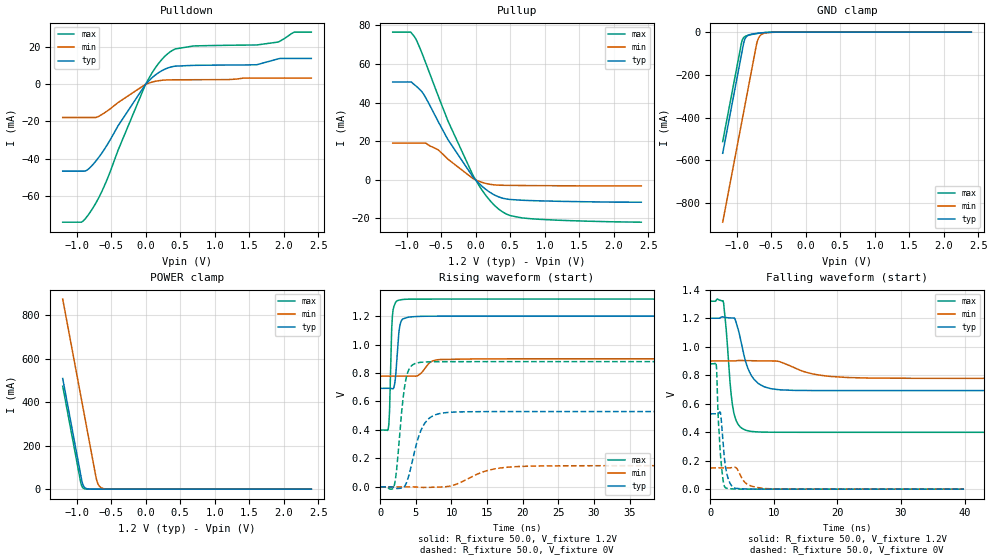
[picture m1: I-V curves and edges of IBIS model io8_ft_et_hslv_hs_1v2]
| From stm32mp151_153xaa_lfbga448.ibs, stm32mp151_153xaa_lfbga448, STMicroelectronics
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[Model]   io8_ft_et_hslv_hs_1v2
Model_type I/O
Polarity   Non-Inverting
Enable   Active-Low
| CAP_THRESHOLD on pad IOFT is "UDTCAPC" :
| Rising=20.00f vddiom   Falling=80.00f vddiom
| C_comp min and max val. don't necessarily correlate with the min and max pvt
| but are the smallest and greatest pad capacitance found.
| var   typ   min   max
C_comp   3.10945pF  3.08840pF  3.12935pF
|C_comp_pullup   1.82175pF  1.58940pF  1.75355pF
|C_comp_pulldown   1.28770pF  1.49900pF  1.37580pF
Vinl = 360.0mV
Vinh = 792.0mV
Vmeas = 600.0mV   | Reference voltage for timing measurements
Cref  = 50.0pF   | Timing specification test load capacitance value
Rref  = 100.0MOhm   | Timing specification test load resistance value
Vref  = 0V   | Timing specification test load voltage
[Model Spec]
| TIME_THRESHOLD on pin ZIV11 is "CMOS" :
| Rising=40.00f vdd   Falling=60.00f vdd
Vinl 463.60000mV 362.60000mV 506.60000mV
Vinh 741.40000mV 545.40000mV 817.40000mV
| variable   typ   min   max
[Temperature Range] 25.0 140.0 -40.0
| variable   typ   min   max
[Voltage Range] 1.2V 900.0mV 1.32V
| variable   typ   min   max
[POWER Clamp Reference] 1.2V 900.0mV 1.32V
| variable   typ   min   max
[GND Clamp Reference] 0V 0V 0V
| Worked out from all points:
|   slope of the pulldown table from 0 to 0.18 V, typ, clamps not added: 30 ohm
|   slope of the pullup table from 0 to 0.18 V, typ, clamps not added: 31.1 ohm
|   GND clamp passes 1 mA (typ) near -0.52 V on its own axis
|   POWER clamp passes 1 mA (typ) near -0.83 V on its own axis
|   rising waveform, R_fixture 50.0, V_fixture 1.2V: 20-80 % time 469ps typ, 1.22ns min, 303ps max; typ from 0.692 V to 1.2 V
|   falling waveform, R_fixture 50.0, V_fixture 1.2V: 20-80 % time 1.99ns typ, 4.89ns min, 1.04ns max; typ from 1.2 V to 0.692 V
|   rising waveform, R_fixture 50.0, V_fixture 0V: 20-80 % time 1.81ns typ, 4.17ns min, 1.01ns max; typ from 0 V to 0.529 V
|   falling waveform, R_fixture 50.0, V_fixture 0V: 20-80 % time 776ps typ, 1.52ns min, 630ps max; typ from 0.529 V to 0 V
[POWER Clamp]
-1.2V     508.8mA    874.1mA    473.5mA
-940mV    66.83mA    432.1mA    31.5mA
-930mV    49.83mA    415.1mA    19.15mA
-910mV    22.88mA    381.1mA    7.077mA
-880mV    7.117mA    330.1mA    1.59mA
-830mV    1.017mA    245.1mA    132uA
-720mV    14.05uA    58.12mA    554nA
-690mV    4.373uA    25.03mA    124.8nA
-650mV    922.5nA    8.136mA    17.23nA
-600mV    132.6nA    1.998mA    1.565nA
-490mV    2.857nA    90.92uA    111.8pA
2.4V      0A         0A         0A
[GND Clamp]
-1.2V     -567.2mA   -889.7mA   -512.2mA
-930mV    -108.2mA   -430.7mA   -53.23mA
-920mV    -91.21mA   -413.7mA   -40.49mA
-890mV    -43.51mA   -362.7mA   -23.59mA
-860mV    -22.57mA   -311.7mA   -17.89mA
-810mV    -12.11mA   -226.7mA   -13.23mA
-710mV    -6.053mA   -57.05mA   -7.064mA
-680mV    -4.908mA   -27.37mA   -5.632mA
-640mV    -3.605mA   -11.51mA   -3.985mA
-560mV    -1.665mA   -3.218mA   -1.61mA
-360mV    -34.72uA   -209.4uA   -9.248uA
2.4V      3.415nA    1.206uA    162.7pA
| variable   typ   min   max
[Pullup Reference] 1.2V 900.0mV 1.32V
| variable   typ   min   max
[Pulldown Reference] 0V 0V 0V
[Pullup]
-1.2V     50.71mA    18.99mA    76.55mA
-940mV    50.71mA    18.99mA    76.55mA
-870mV    48.83mA    18.99mA    73.29mA
-760mV    44.8mA     18.99mA    64.11mA
-550mV    30.82mA    15.7mA     44.31mA
-400mV    20.81mA    10.68mA    30.51mA
-40mV     1.605mA    702.6uA    2.512mA
160mV     -5.268mA   -1.975mA   -8.606mA
350mV     -9.04mA    -2.783mA   -15.59mA
510mV     -10.21mA   -2.889mA   -18.61mA
750mV     -10.7mA    -2.975mA   -20.01mA
2.4V      -11.6mA    -3.141mA   -21.96mA
[Pulldown]
-1.2V     -46.7mA    -17.86mA   -74.13mA
-930mV    -46.7mA    -17.86mA   -74.13mA
-770mV    -43.45mA   -17.86mA   -66.94mA
-580mV    -33.98mA   -14.99mA   -53.18mA
0V        0A         -6pA       0A
170mV     5.742mA    1.792mA    10.3mA
340mV     8.972mA    2.348mA    16.97mA
690mV     10.15mA    2.431mA    20.56mA
1.61V     10.49mA    3.333mA    21.11mA
1.92V     13.63mA    3.333mA    22.69mA
2.15V     13.87mA    3.333mA    27.93mA
2.4V      13.87mA    3.333mA    28.03mA
[Ramp]
dV/dt_r 317.41819mV/1.81281ns 89.26304mV/4.16545ns 528.12961mV/1.00938ns
dV/dt_f 304.66736mV/1.99296ns 73.18611mV/4.89232ns 552.41142mV/1.03926ns
R_load = 50.0
| Removed startup time: 0s 0s 0s  .
| Removed end time: 39.9ns.
[Rising Waveform]
R_fixture   = 50.0
V_fixture   = 1.2V
V_fixture_min = 900.0mV
V_fixture_max = 1.32V
0s        692.2mV    778mV      399.3mV
1.2ns     692.5mV    778.1mV    437.4mV
1.6ns     690.8mV    778.1mV    1.109V
1.7ns     689mV      778.1mV    1.198V
2.1ns     752.6mV    778.1mV    1.292V
2.4ns     954.5mV    778.1mV    1.309V
2.9ns     1.16V      778.1mV    1.315V
4ns       1.193V     778.2mV    1.319V
8.3ns     1.2V       894.6mV    1.32V
39.9ns    1.2V       900mV      1.32V
| Removed startup time: 0s 0s 0s  .
| Removed end time: 199.9ns.
[Falling Waveform]
R_fixture   = 50.0
V_fixture   = 1.2V
V_fixture_min = 900.0mV
V_fixture_max = 1.32V
0s        1.2V       900mV      1.32V
2.1ns     1.208V     900mV      1.305V
3.2ns     1.202V     899.8mV    702.1mV
3.9ns     1.193V     900.6mV    502.9mV
5.6ns     889.8mV    902.1mV    413.8mV
6.7ns     782mV      901.2mV    404.4mV
10.8ns    698.1mV    896.7mV    399.5mV
16.1ns    692.5mV    809.2mV    399.3mV
24.9ns    692.2mV    780.2mV    399.3mV
199.9ns   692.2mV    778mV      399.3mV
| Removed startup time: 0s 0s 0s  .
| Removed end time: 199.9ns.
[Rising Waveform]
R_fixture   = 50.0
V_fixture   = 0V
V_fixture_min = 0V
V_fixture_max = 0V
0s        -204.6nV   193.4nV    -4.045uV
1.9ns     -5.602mV   -484.1nV   -2.479mV
2.3ns     -11.76mV   -2.2uV     123.3mV
3.2ns     -6.005mV   -45.89uV   622.1mV
3.7ns     30.96mV    1.074uV    778.9mV
5.9ns     417mV      -4.443mV   876.4mV
8.8ns     519.1mV    -1.016mV   879.7mV
15.7ns    528.7mV    122.4mV    880.1mV
22.2ns    528.9mV    146.3mV    880.2mV
199.9ns   529mV      148.8mV    880.2mV
| Removed startup time: 0s 0s 0s  .
| Removed end time: 39.9ns.
[Falling Waveform]
R_fixture   = 50.0
V_fixture   = 0V
V_fixture_min = 0V
V_fixture_max = 0V
0s        529mV      148.8mV    880.2mV
900ps     529.2mV    148.8mV    891.4mV
1ns       529mV      148.8mV    843.5mV
1.3ns     531.9mV    148.8mV    455.6mV
1.6ns     537.4mV    148.8mV    242.7mV
2.4ns     155.1mV    148.8mV    9.407mV
4.1ns     5.555mV    149.4mV    870.3uV
5.6ns     1.589mV    41.23mV    223.6uV
8.5ns     236.4uV    5.158mV    32.75uV
39.9ns    57.39nV    1.38uV     34.8nV
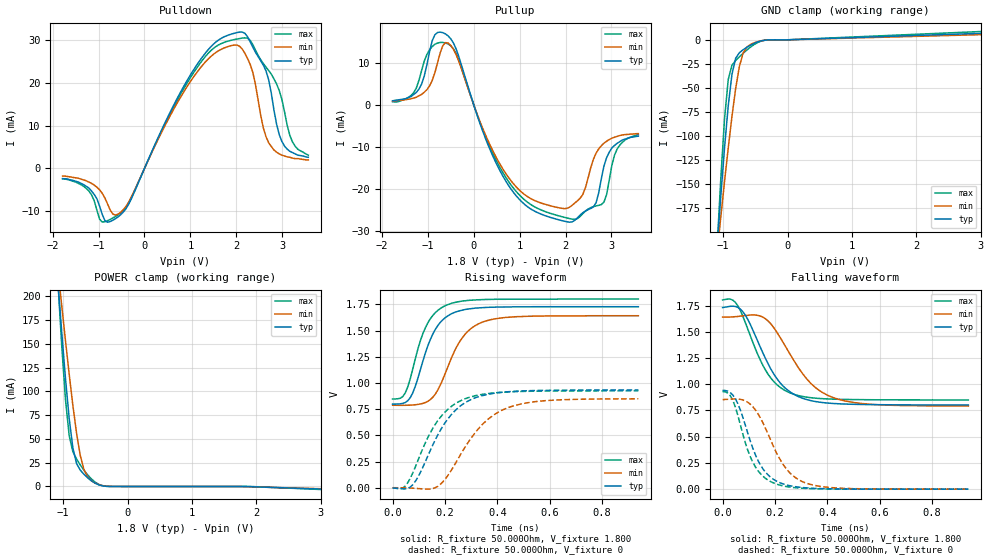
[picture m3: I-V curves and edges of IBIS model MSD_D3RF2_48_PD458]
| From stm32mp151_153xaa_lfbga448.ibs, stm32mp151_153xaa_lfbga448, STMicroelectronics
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[Model] MSD_D3RF2_48_PD458
Model_type   I/O
C_comp 2.372pF   2.291pF   2.493pF
Vinh = 1.150V
Vinl = 650.000mV
Vmeas = 900.000mV
Vref = 900.000mV
[Model Spec]
Vinh   1.150V   1.100V   1.200V
Vinl   650.000mV   600.000mV   700.000mV
Vmeas   900.000mV   850.000mV   950.000mV
Vref   900.000mV   850.000mV   950.000mV
[Temperature Range]   25.000   125.000   -40.000
[Voltage Range]   1.800V   1.700V   1.900V
[GND Clamp Reference]   0.00V   0.00V   0.00V
[Pulldown Reference]   0.00V   0.00V   0.00V
[POWER Clamp Reference]   1.800V   1.700V   1.900V
[Pullup Reference]   1.800V   1.700V   1.900V
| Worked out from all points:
|   slope of the pulldown table from 0 to 0.27 V, typ, clamps not added: 41 ohm
|   slope of the pullup table from 0 to 0.27 V, typ, clamps not added: 32.3 ohm
|   GND clamp passes 1 mA (typ) near -0.40 V on its own axis
|   POWER clamp passes 1 mA (typ) near -0.41 V on its own axis
|   rising waveform, R_fixture 50.000Ohm, V_fixture 1.800: 20-80 % time 82.4ps typ, 101ps min, 76.2ps max; typ from 0.798 V to 1.73 V
|   rising waveform, R_fixture 50.000Ohm, V_fixture 0: 20-80 % time 130ps typ, 153ps min, 123ps max; typ from -0.002 V to 0.934 V
|   falling waveform, R_fixture 50.000Ohm, V_fixture 1.800: 20-80 % time 119ps typ, 144ps min, 107ps max; typ from 1.73 V to 0.802 V
|   falling waveform, R_fixture 50.000Ohm, V_fixture 0: 20-80 % time 87.5ps typ, 108ps min, 79.1ps max; typ from 0.942 V to 0 V
[GND Clamp]
-1.785V   -902mA     -689.4mA   -1.211A
-1.094V   -215mA     -221.2mA   -215.8mA
-1.036V   -162.1mA   -183.9mA   -143.8mA
-978.8mV  -112.5mA   -147.5mA   -82.44mA
-921.2mV  -68.78mA   -112.6mA   -41.33mA
-863.6mV  -35.99mA   -79.83mA   -26.49mA
-806.1mV  -19.21mA   -50.81mA   -21.54mA
-748.5mV  -13.41mA   -27.96mA   -17.69mA
-690.9mV  -10.37mA   -13.94mA   -14.08mA
-575.8mV  -5.623mA   -4.825mA   -7.6mA
-287.9mV  -74.28uA   -124.4uA   -59.6uA
3.57V     8.01mA     6.376mA    10.24mA
[Power Clamp]
-1.77V    883.4mA    690.5mA    1.16A
-1.079V   212.7mA    226.7mA    212.7mA
-1.021V   161.3mA    189.6mA    147.2mA
-963.6mV  113.3mA    153.2mA    91.32mA
-906.1mV  71.44mA    118mA      53.27mA
-848.5mV  40.26mA    84.97mA    36.49mA
-790.9mV  24mA       55.59mA    28.76mA
-733.3mV  17.15mA    32.36mA    22.54mA
-618.2mV  9.062mA    9.82mA     12.07mA
-503mV    3.471mA    3.563mA    4.523mA
-272.7mV  29uA       101.1uA    30.42uA
3.585V    -4.055mA   -3.446mA   -4.875mA
[Pulldown]
-1.785V   -2.4mA     -1.8mA     -2.4mA
-1.209V   -4.6mA     -3.2mA     -5.3mA
-921.2mV  -10.72mA   -5.8mA     -12.52mA
-690.9mV  -12.11mA   -10.65mA   -11.59mA
-518.2mV  -10.82mA   -10.23mA   -10.35mA
1.094V    23.43mA    21.75mA    22.75mA
2.073V    31.84mA    28.54mA    30.34mA
2.361V    28.32mA    22.42mA    28.91mA
2.706V    20.69mA    6mA        22.85mA
2.994V    6.3mA      3.1mA      16.1mA
3.224V    3.7mA      2.4mA      6.2mA
3.57V     2.6mA      2mA        3.1mA
[Pullup]
-1.77V    1mA        900uA      773.7uA
-1.309V   2.5mA      1.647mA    2.937mA
-1.021V   9.6mA      3.642mA    12.02mA
-848.5mV  16.66mA    7.674mA    14.42mA
-618.2mV  16.89mA    14.82mA    14.75mA
763.6mV   -19.22mA   -17.31mA   -18.28mA
2.03V     -27.75mA   -24.55mA   -26.84mA
2.376V    -25.59mA   -21.22mA   -25.8mA
2.606V    -24.21mA   -12.89mA   -24.15mA
2.836V    -14.5mA    -9.058mA   -23.07mA
3.124V    -9.1mA     -7.453mA   -10.44mA
3.585V    -7.4mA     -6.8mA     -7.074mA
[Ramp]
R_load=50.000Ohm
dV/dt_r   557.580mV/107.000ps  509.759mV/128.500ps  562.260mV/100.500ps
dV/dt_f   557.580mV/104.000ps  509.759mV/126.500ps  562.260mV/93.500ps
[Rising waveform]
R_fixture=50.000Ohm
V_fixture=1.800
V_fixture_min=1.700
V_fixture_max=1.900
0s        798.2mV    787.5mV    847.4mV
39ps      804.9mV    786.6mV    870.3mV
68ps      861.5mV    788.2mV    1.045V
96ps      1.039V     794.9mV    1.318V
125ps     1.284V     813mV      1.525V
163ps     1.51V      892.8mV    1.67V
202ps     1.624V     1.097V     1.738V
269ps     1.696V     1.44V      1.782V
355ps     1.72V      1.59V      1.796V
938ps     1.727V     1.641V     1.8V
[Rising waveform]
R_fixture=50.000Ohm
V_fixture=0
0s        -1.68mV    601.3uV    -1.967mV
39ps      -10.41mV   -415.5uV   -1.572mV
77ps      28.99mV    -4.057mV   140mV
135ps     305.6mV    -13.28mV   481mV
173ps     506mV      14.28mV    641.9mV
221ps     687.9mV    154.3mV    769.4mV
278ps     813.5mV    392.7mV    850.1mV
365ps     892.3mV    655.4mV    898.8mV
451ps     917.9mV    773.3mV    915.2mV
938ps     933.5mV    848.5mV    924.7mV
[Falling waveform]
R_fixture=50.000Ohm
V_fixture=1.800
V_fixture_min=1.700
V_fixture_max=1.900
0s        1.731V     1.64V      1.803V
29ps      1.743V     1.641V     1.812V
58ps      1.733V     1.646V     1.749V
96ps      1.619V     1.657V     1.528V
154ps     1.298V     1.639V     1.179V
211ps     1.041V     1.481V     988.1mV
259ps     924.8mV    1.28V      916.3mV
336ps     844.7mV    1.01V      872.1mV
441ps     814.2mV    857.4mV    856.8mV
938ps     802.3mV    792.5mV    850.5mV
[Falling waveform]
R_fixture=50.000Ohm
V_fixture=0
0s        941.6mV    853.6mV    930.2mV
20ps      934.1mV    856.8mV    916mV
39ps      897.6mV    859.4mV    847.6mV
68ps      754.3mV    856.1mV    612.3mV
106ps     457.6mV    809.4mV    307.6mV
154ps     193.7mV    632.3mV    123.7mV
202ps     81.87mV    365.7mV    51.88mV
269ps     27mV       127.4mV    16.2mV
355ps     7.249mV    34.12mV    3.841mV
938ps     21.21uV    36.29uV    0V
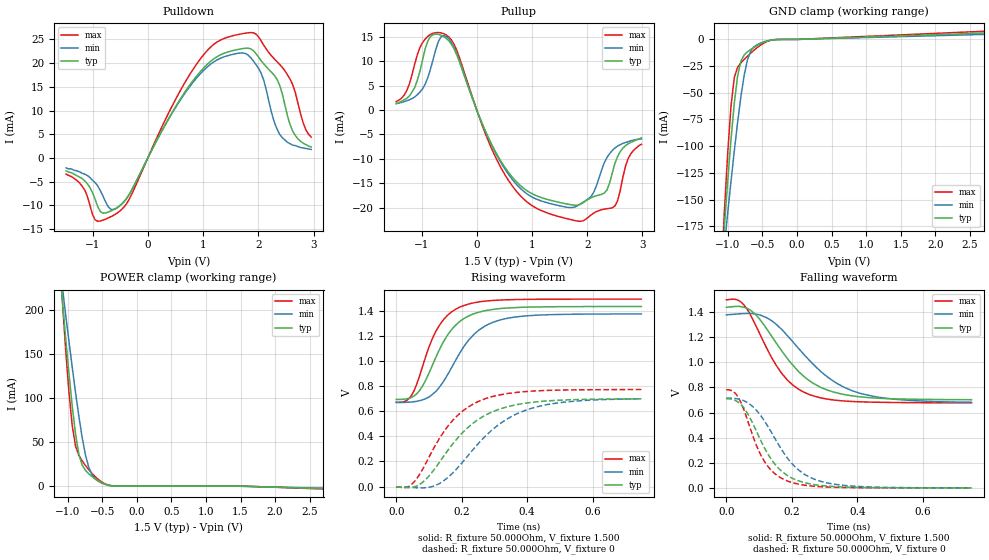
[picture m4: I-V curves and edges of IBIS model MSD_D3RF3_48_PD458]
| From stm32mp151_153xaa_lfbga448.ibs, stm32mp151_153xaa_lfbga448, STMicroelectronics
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[Model] MSD_D3RF3_48_PD458
Model_type   I/O
C_comp 2.385pF   2.303pF   2.507pF
Vinh = 925.000mV
Vinl = 575.000mV
Vmeas = 750.000mV
Vref = 750.000mV
[Model Spec]
Vinh   925.000mV   888.000mV   963.000mV
Vinl   575.000mV   538.000mV   613.000mV
Vmeas   750.000mV   713.000mV   788.000mV
Vref   750.000mV   713.000mV   788.000mV
[Temperature Range]   25.000   125.000   -40.000
[Voltage Range]   1.500V   1.425V   1.575V
[GND Clamp Reference]   0.00V   0.00V   0.00V
[Pulldown Reference]   0.00V   0.00V   0.00V
[POWER Clamp Reference]   1.500V   1.425V   1.575V
[Pullup Reference]   1.500V   1.425V   1.575V
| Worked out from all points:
|   slope of the pulldown table from 0 to 0.225 V, typ, clamps not added: 44.1 ohm
|   slope of the pullup table from 0 to 0.225 V, typ, clamps not added: 37.5 ohm
|   GND clamp passes 1 mA (typ) near -0.40 V on its own axis
|   POWER clamp passes 1 mA (typ) near -0.41 V on its own axis
|   rising waveform, R_fixture 50.000Ohm, V_fixture 1.500: 20-80 % time 93.1ps typ, 110ps min, 79ps max; typ from 0.694 V to 1.44 V
|   rising waveform, R_fixture 50.000Ohm, V_fixture 0: 20-80 % time 149ps typ, 169ps min, 128ps max; typ from -0.003 V to 0.699 V
|   falling waveform, R_fixture 50.000Ohm, V_fixture 1.500: 20-80 % time 139ps typ, 168ps min, 111ps max; typ from 1.44 V to 0.703 V
|   falling waveform, R_fixture 50.000Ohm, V_fixture 0: 20-80 % time 95.2ps typ, 114ps min, 78.5ps max; typ from 0.711 V to 0 V
[GND Clamp]
-1.48V    -594.6mA   -480.3mA   -764mA
-1.098V   -218.6mA   -223.7mA   -220.8mA
-1.05V    -174.4mA   -192.7mA   -160.1mA
-1.002V   -132.3mA   -162.2mA   -105.6mA
-954.6mV  -93.15mA   -132.6mA   -61.94mA
-906.8mV  -59.31mA   -104.2mA   -35.51mA
-859.1mV  -34.06mA   -77.39mA   -25.96mA
-811.4mV  -20.13mA   -53.27mA   -21.92mA
-715.9mV  -11.58mA   -18.88mA   -15.63mA
-572.7mV  -5.513mA   -4.72mA    -7.447mA
-334.1mV  -249.6uA   -317.8uA   -254.1uA
2.959V    6.512mA    5.126mA    8.372mA
[Power Clamp]
-1.459V   578.2mA    479.5mA    723.7mA
-1.077V   211.3mA    225.7mA    210.8mA
-1.03V    168.5mA    194.9mA    156mA
-981.8mV  127.8mA    164.6mA    107.1mA
-934.1mV  90.77mA    134.9mA    68.64mA
-886.4mV  59.26mA    106.4mA    45.51mA
-838.6mV  36.4mA     79.58mA    34.92mA
-743.2mV  18.03mA    35.67mA    23.54mA
-647.7mV  10.86mA    12.93mA    14.5mA
-552.3mV  5.551mA    5.488mA    7.32mA
-313.6mV  97.21uA    230.9uA    114.2uA
2.98V     -3.313mA   -2.778mA   -4.023mA
[Pulldown]
-1.48V    -2.7mA     -2.1mA     -3.4mA
-1.145V   -4.8mA     -3.4mA     -6.7mA
-954.6mV  -8.71mA    -5.2mA     -13.05mA
-811.4mV  -11.64mA   -8.06mA    -13.11mA
-525mV    -10.19mA   -10.28mA   -11.37mA
906.8mV   17.61mA    17.2mA     20.18mA
1.766V    23.15mA    22.05mA    26.32mA
2.052V    20.52mA    17.86mA    24.7mA
2.386V    15.37mA    5mA        19.75mA
2.625V    5.6mA      2.7mA      15.4mA
2.816V    3.1mA      2.1mA      7.3mA
2.959V    2.3mA      1.8mA      4.4mA
[Pullup]
-1.459V   1.3mA      1.357mA    1.729mA
-1.125V   4.6mA      2.671mA    9.4mA
-981.8mV  10.3mA     4.357mA    13.84mA
-838.6mV  15.06mA    8.386mA    15.51mA
-552.3mV  14.69mA    15.08mA    15.38mA
640.9mV   -13.71mA   -14.18mA   -15.51mA
1.834V    -19.47mA   -19.55mA   -22.76mA
2.12V     -17.72mA   -16.78mA   -21.08mA
2.311V    -16.98mA   -10.74mA   -20.29mA
2.502V    -10.9mA    -7.771mA   -19.63mA
2.741V    -6.9mA     -6.486mA   -9.928mA
2.98V     -5.7mA     -5.9mA     -7.014mA
[Ramp]
R_load=50.000Ohm
dV/dt_r   430.230mV/121.500ps  420.209mV/140.000ps  477.210mV/104.000ps
dV/dt_f   430.230mV/118.000ps  420.209mV/142.500ps  477.210mV/95.500ps
[Rising waveform]
R_fixture=50.000Ohm
V_fixture=1.500
V_fixture_min=1.425
V_fixture_max=1.575
0s        694.2mV    669.6mV    671.7mV
39ps      703.1mV    672.3mV    699.9mV
69ps      757.5mV    683mV      862.7mV
100ps     903.4mV    713.2mV    1.111V
123ps     1.041V     762.5mV    1.246V
154ps     1.196V     878.5mV    1.358V
192ps     1.311V     1.054V     1.428V
253ps     1.39V      1.248V     1.472V
330ps     1.421V     1.336V     1.488V
749ps     1.435V     1.376V     1.494V
[Rising waveform]
R_fixture=50.000Ohm
V_fixture=0
0s        -3.058mV   -1.782mV   -3.355mV
31ps      -8.593mV   -5.329mV   -6.138mV
54ps      -4.024mV   -8.678mV   34.03mV
85ps      43.65mV    -10.32mV   158mV
131ps     189.5mV    21.94mV    378.7mV
199ps     419.2mV    182.5mV    593.7mV
261ps     551.7mV    370.8mV    689mV
337ps     633.9mV    535.7mV    740mV
429ps     675.3mV    635.1mV    762.7mV
749ps     698.9mV    698.9mV    773.3mV
[Falling waveform]
R_fixture=50.000Ohm
V_fixture=1.500
V_fixture_min=1.425
V_fixture_max=1.575
0s        1.439V     1.379V     1.498V
46ps      1.444V     1.388V     1.478V
85ps      1.391V     1.387V     1.321V
123ps     1.268V     1.356V     1.115V
169ps     1.093V     1.263V     913.1mV
245ps     870.5mV    1.041V     753.3mV
330ps     761.6mV    845.7mV    699.6mV
414ps     724mV      749.5mV    685.3mV
513ps     709.5mV    706.3mV    680.3mV
749ps     702.6mV    681.9mV    677.5mV
[Falling waveform]
R_fixture=50.000Ohm
V_fixture=0
0s        710.9mV    714.5mV    782mV
23ps      702.1mV    713.3mV    764.8mV
39ps      677.1mV    707mV      710.1mV
85ps      490.6mV    636.7mV    385.5mV
108ps     362.2mV    565mV      248.4mV
131ps     252.4mV    472.1mV    158.1mV
184ps     103.2mV    247.1mV    57.7mV
238ps     42.31mV    109.3mV    21.92mV
322ps     11.63mV    32.46mV    5.154mV
749ps     79.97uV    222.5uV    -2.137uV
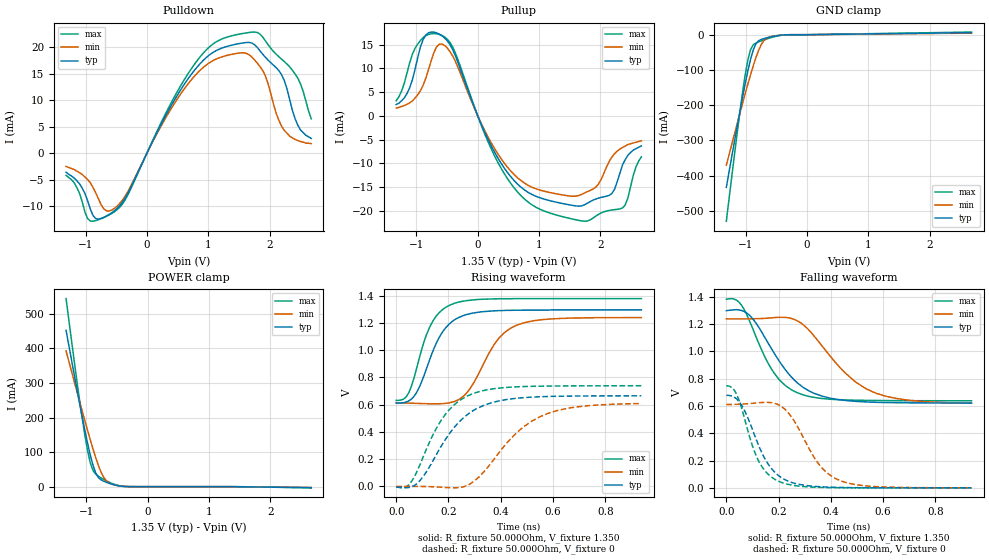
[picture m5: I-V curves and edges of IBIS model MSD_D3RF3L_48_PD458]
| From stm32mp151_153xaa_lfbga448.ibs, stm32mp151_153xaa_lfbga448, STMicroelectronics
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[Model] MSD_D3RF3L_48_PD458
Model_type   I/O
C_comp 2.393pF   2.308pF   2.516pF
Vinh = 810.000mV
Vinl = 540.000mV
Vmeas = 675.000mV
Vref = 675.000mV
[Model Spec]
Vinh   810.000mV   777.000mV   860.000mV
Vinl   540.000mV   507.000mV   590.000mV
Vmeas   675.000mV   642.000mV   725.000mV
Vref   675.000mV   642.000mV   725.000mV
[Temperature Range]   25.000   125.000   -40.000
[Voltage Range]   1.350V   1.283V   1.450V
[GND Clamp Reference]   0.00V   0.00V   0.00V
[Pulldown Reference]   0.00V   0.00V   0.00V
[POWER Clamp Reference]   1.350V   1.283V   1.450V
[Pullup Reference]   1.350V   1.283V   1.450V
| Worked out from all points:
|   slope of the pulldown table from 0 to 0.203 V, typ, clamps not added: 42.2 ohm
|   slope of the pullup table from 0 to 0.203 V, typ, clamps not added: 34.5 ohm
|   GND clamp passes 1 mA (typ) near -0.40 V on its own axis
|   POWER clamp passes 1 mA (typ) near -0.41 V on its own axis
|   rising waveform, R_fixture 50.000Ohm, V_fixture 1.350: 20-80 % time 94.1ps typ, 117ps min, 79.7ps max; typ from 0.612 V to 1.29 V
|   rising waveform, R_fixture 50.000Ohm, V_fixture 0: 20-80 % time 152ps typ, 184ps min, 130ps max; typ from -0.004 V to 0.665 V
|   falling waveform, R_fixture 50.000Ohm, V_fixture 1.350: 20-80 % time 152ps typ, 185ps min, 119ps max; typ from 1.3 V to 0.621 V
|   falling waveform, R_fixture 50.000Ohm, V_fixture 0: 20-80 % time 99.8ps typ, 118ps min, 82.4ps max; typ from 0.678 V to 0 V
[GND Clamp]
-1.318V   -433.4mA   -370.8mA   -529.5mA
-1.142V   -261.1mA   -253.1mA   -280.7mA
-1.055V   -178.6mA   -195.6mA   -165.7mA
-1.011V   -139.5mA   -167.5mA   -114.5mA
-966.7mV  -102.7mA   -140mA     -71.69mA
-922.7mV  -69.83mA   -113.5mA   -42.04mA
-878.8mV  -43.2mA    -88.17mA   -28.64mA
-834.9mV  -25.59mA   -64.74mA   -23.69mA
-790.9mV  -17.08mA   -44.07mA   -20.49mA
-703mV    -10.94mA   -16.13mA   -14.83mA
-527.3mV  -3.964mA   -3.359mA   -5.286mA
2.68V     5.803mA    4.518mA    7.521mA
[Power Clamp]
-1.33V    452.5mA    393mA      544.4mA
-1.111V   242.2mA    247.4mA    251.2mA
-1.023V   162.6mA    190.5mA    148.3mA
-978.8mV  125.4mA    162.5mA    103.8mA
-934.9mV  91.31mA    135.3mA    68.32mA
-890.9mV  61.93mA    108.9mA    46.71mA
-847mV    39.6mA     84.01mA    36.22mA
-803mV    26.26mA    61.23mA    30.15mA
-715.1mV  15.61mA    26.48mA    20.68mA
-671.2mV  12.4mA     16.4mA     16.54mA
-407.6mV  894uA      1.169mA    1.092mA
2.668V    -2.917mA   -2.431mA   -3.468mA
[Pulldown]
-1.318V   -3.6mA     -2.5mA     -4.2mA
-1.098V   -5.8mA     -3.7mA     -7.6mA
-922.7mV  -10.54mA   -5.6mA     -12.83mA
-703mV    -12.12mA   -10.54mA   -12.17mA
-483.3mV  -10.41mA   -9.976mA   -10.65mA
790.9mV   15.9mA     14.77mA    17.06mA
1.582V    20.87mA    18.98mA    22.68mA
1.889V    18.71mA    15.62mA    21.96mA
2.197V    14.84mA    5.1mA      17.77mA
2.329V    10.1mA     3.2mA      16.32mA
2.461V    5.3mA      2.4mA      14.2mA
2.68V     2.8mA      1.8mA      6.5mA
[Pullup]
-1.33V    2.4mA      1.652mA    3.207mA
-1.023V   9.8mA      3.767mA    14.27mA
-890.9mV  16.12mA    6.482mA    16.52mA
-715.1mV  17.65mA    13.35mA    17.35mA
-451.5mV  14.98mA    13.54mA    15.46mA
295.4mV   -8.125mA   -7.33mA    -8.964mA
910.6mV   -16.72mA   -15.17mA   -18.95mA
1.702V    -18.92mA   -16.49mA   -22.14mA
1.965V    -17.33mA   -14.42mA   -20.77mA
2.185V    -16.37mA   -8.694mA   -19.82mA
2.361V    -10.3mA    -6.643mA   -19.39mA
2.668V    -6.3mA     -5.248mA   -8.621mA
[Ramp]
R_load=50.000Ohm
dV/dt_r   402.030mV/123.500ps  370.259mV/152.000ps  443.850mV/105.500ps
dV/dt_f   402.030mV/125.500ps  370.319mV/153.500ps  443.850mV/100.500ps
[Rising waveform]
R_fixture=50.000Ohm
V_fixture=1.350
V_fixture_min=1.283
V_fixture_max=1.450
0s        611.7mV    614mV      631.4mV
39ps      620mV      612mV      659.5mV
77ps      685.9mV    609.6mV    858.1mV
135ps     966.3mV    606.4mV    1.195V
173ps     1.121V     607.4mV    1.29V
211ps     1.205V     617.5mV    1.335V
278ps     1.265V     705.5mV    1.365V
374ps     1.288V     1.039V     1.376V
460ps     1.293V     1.182V     1.378V
938ps     1.295V     1.239V     1.378V
[Rising waveform]
R_fixture=50.000Ohm
V_fixture=0
0s        -4.091mV   598.5uV    -4.132mV
48ps      -7.821mV   818.6uV    11.8mV
87ps      35.92mV    511.1uV    142.1mV
135ps     169.4mV    -1.636mV   357.1mV
183ps     329.4mV    -6.49mV    515.8mV
288ps     548.8mV    25.88mV    677mV
460ps     647mV      392mV      731mV
547ps     658mV      509mV      735.5mV
681ps     663.3mV    581.2mV    737.9mV
938ps     665.1mV    608.3mV    739.1mV
[Falling waveform]
R_fixture=50.000Ohm
V_fixture=1.350
V_fixture_min=1.283
V_fixture_max=1.450
0s        1.299V     1.239V     1.382V
48ps      1.304V     1.238V     1.362V
87ps      1.268V     1.238V     1.231V
183ps     987.3mV    1.248V     841.3mV
278ps     759.8mV    1.217V     692.1mV
374ps     668.2mV    1.021V     653.3mV
451ps     641.5mV    849.6mV    644.5mV
537ps     629.4mV    724.3mV    641.1mV
690ps     623.3mV    644.3mV    638.8mV
938ps     621.2mV    620.4mV    638.1mV
[Falling waveform]
R_fixture=50.000Ohm
V_fixture=0
0s        678.4mV    610.6mV    748mV
39ps      652.7mV    611.9mV    688mV
77ps      537.1mV    615.9mV    455.8mV
125ps     304.2mV    623.8mV    191.4mV
202ps     86.15mV    606.6mV    46.57mV
259ps     34.34mV    492.8mV    17.43mV
355ps     8.469mV    170.5mV    3.51mV
432ps     2.951mV    56mV       1.024mV
575ps     424.9uV    8.829mV    185.1uV
938ps     18.53uV    178.8uV    9.656uV
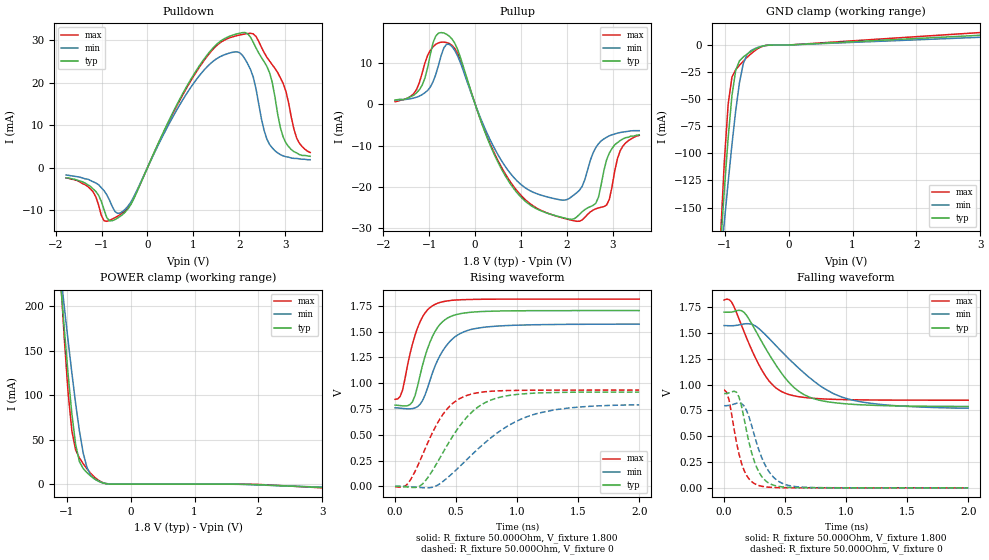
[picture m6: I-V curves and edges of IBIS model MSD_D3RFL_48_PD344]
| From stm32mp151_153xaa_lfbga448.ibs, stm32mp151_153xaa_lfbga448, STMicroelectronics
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[Model] MSD_D3RFL_48_PD344
Model_type   I/O
C_comp 2.313pF   2.231pF   2.434pF
Vinh = 1.440V
Vinl = 360.000mV
Vmeas = 900.000mV
Vref = 900.000mV
[Model Spec]
Vinh   1.440V   1.365V   1.515V
Vinl   360.000mV   285.000mV   435.000mV
Vmeas   900.000mV   825.000mV   975.000mV
Vref   900.000mV   825.000mV   975.000mV
[Temperature Range]   25.000   125.000   -40.000
[Voltage Range]   1.800V   1.650V   1.950V
[GND Clamp Reference]   0.00V   0.00V   0.00V
[Pulldown Reference]   0.00V   0.00V   0.00V
[POWER Clamp Reference]   1.800V   1.650V   1.950V
[Pullup Reference]   1.800V   1.650V   1.950V
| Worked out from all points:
|   slope of the pulldown table from 0 to 0.27 V, typ, clamps not added: 41 ohm
|   slope of the pullup table from 0 to 0.27 V, typ, clamps not added: 32.3 ohm
|   GND clamp passes 1 mA (typ) near -0.40 V on its own axis
|   POWER clamp passes 1 mA (typ) near -0.41 V on its own axis
|   rising waveform, R_fixture 50.000Ohm, V_fixture 1.800: 20-80 % time 153ps typ, 197ps min, 135ps max; typ from 0.788 V to 1.7 V
|   rising waveform, R_fixture 50.000Ohm, V_fixture 0: 20-80 % time 318ps typ, 497ps min, 244ps max; typ from 0.001 V to 0.914 V
|   falling waveform, R_fixture 50.000Ohm, V_fixture 1.800: 20-80 % time 314ps typ, 468ps min, 237ps max; typ from 1.7 V to 0.789 V
|   falling waveform, R_fixture 50.000Ohm, V_fixture 0: 20-80 % time 120ps typ, 149ps min, 103ps max; typ from 0.914 V to 0 V
[GND Clamp]
-1.773V   -888.9mA   -680.4mA   -1.192A
-1.064V   -186.6mA   -201.2mA   -176.5mA
-1.005V   -133.9mA   -163.4mA   -107.6mA
-945.5mV  -85.9mA    -126.8mA   -54.95mA
-886.4mV  -46.93mA   -92.19mA   -29.68mA
-827.3mV  -23.3mA    -60.73mA   -22.78mA
-768.2mV  -14.61mA   -34.72mA   -18.7mA
-709.1mV  -11.06mA   -17.22mA   -14.97mA
-650mV    -8.422mA   -8.803mA   -11.46mA
-590.9mV  -6.076mA   -5.313mA   -8.239mA
-295.4mV  -88.77uA   -143.5uA   -73.5uA
3.545V    10.61mA    8.421mA    13.59mA
[Power Clamp]
-1.745V   858.6mA    673.1mA    1.125A
-1.095V   227.6mA    237.2mA    232.3mA
-1.036V   174.1mA    199mA      163.4mA
-977.3mV  123.8mA    161.5mA    103.2mA
-918.2mV  79.21mA    125.1mA    60.01mA
-859.1mV  44.65mA    90.69mA    38.57mA
-800mV    25.43mA    59.89mA    29.57mA
-740.9mV  17.63mA    35.09mA    23.08mA
-681.8mV  12.98mA    18.74mA    17.35mA
-504.5mV  3.459mA    3.556mA    4.539mA
-327.3mV  139uA      305.9uA    180.2uA
3.573V    -5.368mA   -4.664mA   -6.265mA
[Pulldown]
-1.773V   -2.4mA     -1.7mA     -2.4mA
-1.182V   -5mA       -3.3mA     -5.7mA
-945.5mV  -9.87mA    -5.4mA     -12.48mA
-531.8mV  -10.94mA   -10.23mA   -10.54mA
1.064V    22.92mA    20.76mA    22.57mA
1.595V    29.86mA    26.24mA    29.55mA
2.068V    31.84mA    26.53mA    31.41mA
2.305V    29.56mA    21.37mA    31.55mA
2.659V    22.44mA    5.5mA      25.16mA
3.014V    5.9mA      2.6mA      18.1mA
3.25V     3.5mA      2.2mA      7mA
3.545V    2.7mA      1.9mA      3.6mA
[Pullup]
-1.745V   1mA        900uA      600uA
-1.332V   2.2mA      1.508mA    2.623mA
-1.036V   8.8mA      3.323mA    11.79mA
-859.1mV  16.47mA    7.155mA    14.48mA
-622.7mV  16.92mA    14.49mA    14.91mA
-386.4mV  13.34mA    11.77mA    12.34mA
795.5mV   -19.73mA   -17.13mA   -19.24mA
2.214V    -27.27mA   -21.4mA    -28.32mA
2.745V    -19.44mA   -8.877mA   -24.91mA
2.923V    -11.8mA    -7.638mA   -23mA
3.041V    -9.8mA     -7.192mA   -16.09mA
3.573V    -7.4mA     -6.4mA     -7.554mA
[Ramp]
R_load=50.000Ohm
dV/dt_r   549.090mV/236.000ps  479.819mV/348.000ps  569.640mV/189.500ps
dV/dt_f   548.999mV/217.500ps  479.216mV/310.000ps  569.640mV/169.000ps
[Rising waveform]
R_fixture=50.000Ohm
V_fixture=1.800
V_fixture_min=1.650
V_fixture_max=1.950
0s        788mV      762mV      843.8mV
41ps      783.6mV    758.3mV    869.6mV
62ps      780.6mV    755.8mV    935.1mV
143ps     820.7mV    754.4mV    1.381V
225ps     1.174V     831.9mV    1.643V
286ps     1.398V     1.027V     1.733V
348ps     1.54V      1.222V     1.775V
470ps     1.654V     1.429V     1.804V
654ps     1.691V     1.529V     1.813V
2ns       1.704V     1.573V     1.815V
[Rising waveform]
R_fixture=50.000Ohm
V_fixture=0
0s        1.046mV    1.108mV    -2.68mV
103ps     -5.792mV   -1.227mV   25.31mV
225ps     23.81mV    -12.24mV   306mV
388ps     318.9mV    44.01mV    691.5mV
470ps     482mV      126.5mV    802.7mV
572ps     648.6mV    241.7mV    875.1mV
776ps     832.6mV    462.9mV    921.2mV
1.103ns   901.3mV    684.7mV    931.9mV
1.43ns    912.5mV    760.9mV    933.4mV
2ns       914.5mV    789.7mV    933.5mV
[Falling waveform]
R_fixture=50.000Ohm
V_fixture=1.800
V_fixture_min=1.650
V_fixture_max=1.950
0s        1.703V     1.573V     1.82V
62ps      1.704V     1.571V     1.8V
164ps     1.7V       1.589V     1.512V
246ps     1.549V     1.576V     1.287V
348ps     1.336V     1.473V     1.069V
491ps     1.079V     1.298V     921.9mV
695ps     881.2mV    1.073V     871.5mV
981ps     816.1mV    873.5mV    855.2mV
1.369ns   795.2mV    799.4mV    850.6mV
2ns       788.9mV    772.9mV    849.7mV
[Falling waveform]
R_fixture=50.000Ohm
V_fixture=0
0s        913.7mV    795.8mV    949mV
41ps      920.5mV    799.3mV    850.5mV
82ps      936.8mV    812.2mV    569.4mV
123ps     878.3mV    823.2mV    324.1mV
184ps     551.3mV    751mV      121.4mV
266ps     200.9mV    436.6mV    30.71mV
327ps     83.22mV    243.4mV    11.38mV
388ps     33.61mV    125.2mV    4.611mV
531ps     4.901mV    22.74mV    784.4uV
2ns       14.11uV    88.8uV     0V
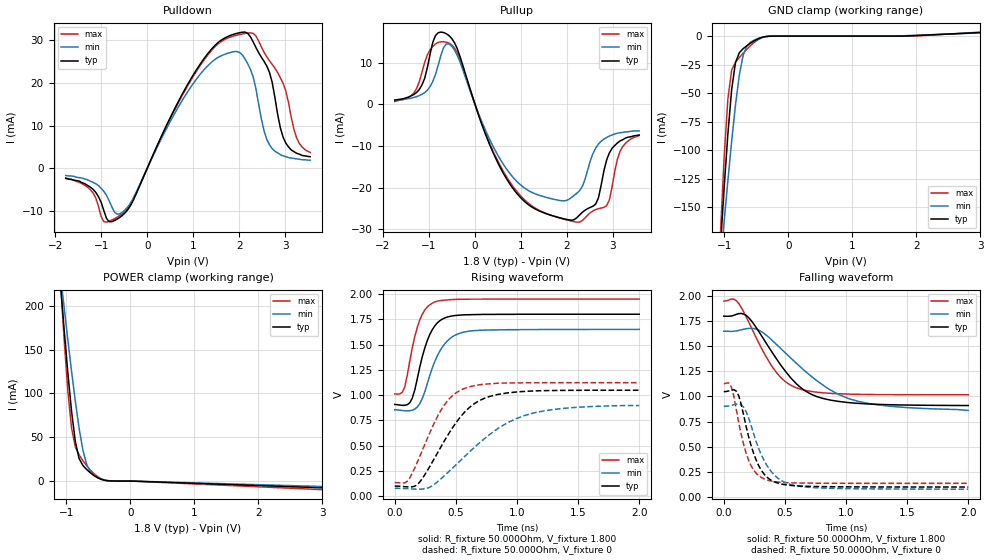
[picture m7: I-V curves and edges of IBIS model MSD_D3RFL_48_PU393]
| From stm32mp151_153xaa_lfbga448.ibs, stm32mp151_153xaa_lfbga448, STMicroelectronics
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[Model] MSD_D3RFL_48_PU393
Model_type   I/O
C_comp 2.345pF   2.262pF   2.468pF
Vinh = 1.440V
Vinl = 360.000mV
Vmeas = 900.000mV
Vref = 900.000mV
[Model Spec]
Vinh   1.440V   1.365V   1.515V
Vinl   360.000mV   285.000mV   435.000mV
Vmeas   900.000mV   825.000mV   975.000mV
Vref   900.000mV   825.000mV   975.000mV
[Temperature Range]   25.000   125.000   -40.000
[Voltage Range]   1.800V   1.650V   1.950V
[GND Clamp Reference]   0.00V   0.00V   0.00V
[Pulldown Reference]   0.00V   0.00V   0.00V
[POWER Clamp Reference]   1.800V   1.650V   1.950V
[Pullup Reference]   1.800V   1.650V   1.950V
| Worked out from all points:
|   slope of the pulldown table from 0 to 0.27 V, typ, clamps not added: 41 ohm
|   slope of the pullup table from 0 to 0.27 V, typ, clamps not added: 32.3 ohm
|   GND clamp passes 1 mA (typ) near -0.40 V on its own axis
|   POWER clamp passes 1 mA (typ) near -0.41 V on its own axis
|   rising waveform, R_fixture 50.000Ohm, V_fixture 1.800: 20-80 % time 126ps typ, 159ps min, 108ps max; typ from 0.907 V to 1.8 V
|   rising waveform, R_fixture 50.000Ohm, V_fixture 0: 20-80 % time 310ps typ, 493ps min, 237ps max; typ from 0.099 V to 1.05 V
|   falling waveform, R_fixture 50.000Ohm, V_fixture 1.800: 20-80 % time 331ps typ, 488ps min, 261ps max; typ from 1.8 V to 0.91 V
|   falling waveform, R_fixture 50.000Ohm, V_fixture 0: 20-80 % time 142ps typ, 179ps min, 121ps max; typ from 1.05 V to 0.098 V
[GND Clamp]
-1.773V   -889.4mA   -680.7mA   -1.193A
-1.064V   -186.7mA   -201.3mA   -176.7mA
-1.005V   -134.1mA   -163.5mA   -107.8mA
-945.5mV  -86.04mA   -126.9mA   -55.15mA
-886.4mV  -47.05mA   -92.27mA   -29.85mA
-827.3mV  -23.42mA   -60.8mA    -22.93mA
-768.2mV  -14.7mA    -34.78mA   -18.83mA
-709.1mV  -11.14mA   -17.27mA   -15.08mA
-650mV    -8.478mA   -8.842mA   -11.56mA
-531.8mV  -4.062mA   -3.429mA   -5.435mA
-295.4mV  -87.03uA   -138.4uA   -73.43uA
3.545V    4.546mA    4.01mA     5.269mA
[Power Clamp]
-1.745V   859.1mA    673.7mA    1.125A
-1.095V   227.9mA    237.5mA    232.6mA
-1.036V   174.4mA    199.2mA    163.7mA
-977.3mV  124.1mA    161.6mA    103.4mA
-918.2mV  79.4mA     125.2mA    60.23mA
-859.1mV  44.82mA    90.86mA    38.77mA
-800mV    25.57mA    60.04mA    29.73mA
-740.9mV  17.75mA    35.23mA    23.22mA
-681.8mV  13.08mA    18.86mA    17.47mA
-504.5mV  3.502mA    3.615mA    4.593mA
-327.3mV  148.8uA    326.5uA    188.9uA
3.573V    -9.22mA    -7.449mA   -11.73mA
[Pulldown]
-1.773V   -2.3mA     -1.7mA     -2.4mA
-1.182V   -4.9mA     -3.3mA     -5.7mA
-945.5mV  -9.87mA    -5.4mA     -12.48mA
-827.3mV  -12.5mA    -7.61mA    -12.4mA
-531.8mV  -10.94mA   -10.24mA   -10.54mA
1.123V    23.9mA     21.59mA    23.56mA
2.068V    31.83mA    26.53mA    31.41mA
2.305V    29.56mA    21.37mA    31.55mA
2.659V    22.44mA    5.5mA      25.16mA
3.014V    5.9mA      2.7mA      18.1mA
3.25V     3.5mA      2.2mA      7.1mA
3.545V    2.7mA      1.9mA      3.7mA
[Pullup]
-1.745V   1mA        953.9uA    646.2uA
-1.332V   2.3mA      1.608mA    2.669mA
-1.036V   8.8mA      3.377mA    11.85mA
-859.1mV  16.47mA    7.15mA     14.48mA
-622.7mV  16.92mA    14.48mA    14.9mA
-386.4mV  13.34mA    11.77mA    12.34mA
795.5mV   -19.73mA   -17.13mA   -19.23mA
2.214V    -27.27mA   -21.39mA   -28.32mA
2.745V    -19.47mA   -8.877mA   -24.91mA
2.982V    -10.6mA    -7.392mA   -19.95mA
3.159V    -8.8mA     -6.846mA   -11.25mA
3.573V    -7.4mA     -6.4mA     -7.508mA
[Ramp]
R_load=50.000Ohm
dV/dt_r   552.645mV/218.000ps  483.858mV/326.500ps  576.600mV/173.000ps
dV/dt_f   552.486mV/237.500ps  481.761mV/329.000ps  576.570mV/191.500ps
[Rising waveform]
R_fixture=50.000Ohm
V_fixture=1.800
V_fixture_min=1.650
V_fixture_max=1.950
0s        907.4mV    855.3mV    1.012V
62ps      898.4mV    847.4mV    1.028V
82ps      898.3mV    845mV      1.082V
143ps     968.4mV    850.4mV    1.466V
225ps     1.379V     964.8mV    1.799V
266ps     1.539V     1.113V     1.872V
327ps     1.684V     1.331V     1.921V
450ps     1.778V     1.558V     1.944V
613ps     1.795V     1.633V     1.949V
2ns       1.8V       1.65V      1.95V
[Rising waveform]
R_fixture=50.000Ohm
V_fixture=0
0s        99.25mV    77.46mV    135mV
103ps     91.93mV    73.99mV    147.1mV
205ps     140.6mV    68.99mV    393.6mV
286ps     292.4mV    87.98mV    625.7mV
388ps     509.6mV    182.4mV    869.4mV
552ps     805.1mV    369.6mV    1.057V
736ps     969.3mV    570.7mV    1.108V
1.062ns   1.036V     797.8mV    1.122V
1.409ns   1.046V     871.2mV    1.123V
2ns       1.048V     896.6mV    1.123V
[Falling waveform]
R_fixture=50.000Ohm
V_fixture=1.800
V_fixture_min=1.650
V_fixture_max=1.950
0s        1.799V     1.649V     1.948V
103ps     1.817V     1.652V     1.952V
184ps     1.806V     1.674V     1.79V
286ps     1.647V     1.661V     1.533V
409ps     1.414V     1.543V     1.274V
491ps     1.271V     1.448V     1.16V
593ps     1.127V     1.331V     1.086V
776ps     992.9mV    1.144V     1.04V
1.103ns   930.7mV    949.9mV    1.021V
2ns       909.5mV    860.3mV    1.016V
[Falling waveform]
R_fixture=50.000Ohm
V_fixture=0
0s        1.048V     901.3mV    1.126V
62ps      1.063V     910.7mV    1.095V
123ps     1.004V     924.5mV    734.4mV
164ps     804.8mV    889.3mV    514.4mV
205ps     590.8mV    779.9mV    359.2mV
266ps     363.9mV    545.7mV    234mV
327ps     230.9mV    368.9mV    180.8mV
450ps     134.5mV    179.2mV    147.2mV
613ps     108.9mV    106.7mV    138.5mV
2ns       98.33mV    77.03mV    135mV
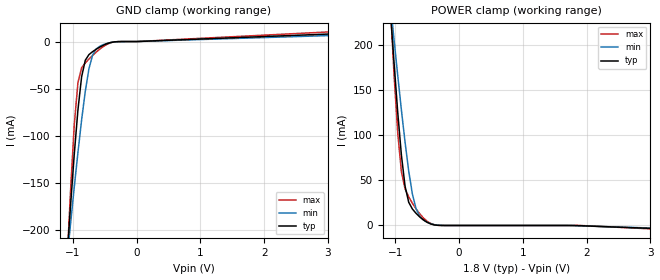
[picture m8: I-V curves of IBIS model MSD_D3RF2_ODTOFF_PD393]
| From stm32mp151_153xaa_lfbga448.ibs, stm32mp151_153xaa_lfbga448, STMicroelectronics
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[Model] MSD_D3RF2_ODTOFF_PD393
Model_type   Input
C_comp 2.343pF   2.262pF   2.463pF
Vinh = 1.150V
Vinl = 650.000mV
[Temperature Range]   25.000   125.000   -40.000
[Voltage Range]   1.800V   1.700V   1.900V
[GND Clamp Reference]   0.00V   0.00V   0.00V
[POWER Clamp Reference]   1.800V   1.700V   1.900V
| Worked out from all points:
|   GND clamp passes 1 mA (typ) near -0.40 V on its own axis
|   POWER clamp passes 1 mA (typ) near -0.41 V on its own axis
[GND Clamp]
-1.785V   -963.3mA   -721.1mA   -1.333A
-1.094V   -229.8mA   -231.6mA   -237.1mA
-1.036V   -172.9mA   -192.5mA   -156.7mA
-978.8mV  -119.5mA   -154.3mA   -88.37mA
-921.2mV  -72.51mA   -117.6mA   -43.58mA
-863.6mV  -37.48mA   -83.21mA   -27.91mA
-806.1mV  -19.88mA   -52.74mA   -22.66mA
-748.5mV  -13.85mA   -28.85mA   -18.57mA
-690.9mV  -10.68mA   -14.28mA   -14.73mA
-575.8mV  -5.748mA   -4.894mA   -7.87mA
-287.9mV  -72.88uA   -122.8uA   -58.4uA
3.57V     9.417mA    7.494mA    12.07mA
[Power Clamp]
-1.77V    980.1mA    743.3mA    1.343A
-1.079V   237.7mA    245.3mA    243.9mA
-1.021V   179.6mA    205.4mA    166.9mA
-963.6mV  125.3mA    166.1mA    102.6mA
-906.1mV  78.06mA    128mA      59.53mA
-848.5mV  43.4mA     92.06mA    40.56mA
-790.9mV  25.66mA    60.03mA    31.66mA
-733.3mV  18.21mA    34.7mA     24.56mA
-618.2mV  9.467mA    10.25mA    12.87mA
-503mV    3.546mA    3.626mA    4.685mA
-272.7mV  28uA       96.32uA    28.78uA
3.585V    -4.769mA   -4.046mA   -5.745mA
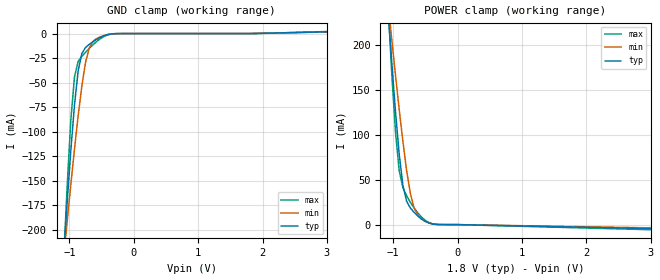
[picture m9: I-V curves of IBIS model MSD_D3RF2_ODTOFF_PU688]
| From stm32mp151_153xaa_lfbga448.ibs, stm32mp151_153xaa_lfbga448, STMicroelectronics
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[Model] MSD_D3RF2_ODTOFF_PU688
Model_type   Input
C_comp 2.432pF   2.350pF   2.555pF
Vinh = 1.150V
Vinl = 650.000mV
[Temperature Range]   25.000   125.000   -40.000
[Voltage Range]   1.800V   1.700V   1.900V
[GND Clamp Reference]   0.00V   0.00V   0.00V
[POWER Clamp Reference]   1.800V   1.700V   1.900V
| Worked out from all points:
|   GND clamp passes 1 mA (typ) near -0.40 V on its own axis
|   POWER clamp passes 1 mA (typ) near -0.41 V on its own axis
[GND Clamp]
-1.785V   -964.7mA   -722.1mA   -1.335A
-1.094V   -230.4mA   -232mA     -237.8mA
-1.036V   -173.5mA   -192.9mA   -157.4mA
-978.8mV  -120.1mA   -154.7mA   -89.04mA
-921.2mV  -72.95mA   -117.9mA   -44.17mA
-863.6mV  -37.88mA   -83.52mA   -28.43mA
-806.1mV  -20.22mA   -53.02mA   -23.12mA
-748.5mV  -14.15mA   -29.09mA   -18.96mA
-690.9mV  -10.93mA   -14.47mA   -15.06mA
-575.8mV  -5.899mA   -5.015mA   -8.073mA
-287.9mV  -76uA      -125uA     -61.99uA
3.57V     2.655mA    2.283mA    3.179mA
[Power Clamp]
-1.77V    981.5mA    744.6mA    1.345A
-1.079V   238.3mA    245.9mA    244.8mA
-1.021V   180.3mA    206mA      167.6mA
-963.6mV  125.9mA    166.6mA    103.3mA
-906.1mV  78.55mA    128.4mA    60.14mA
-848.5mV  43.84mA    92.47mA    41.09mA
-790.9mV  26.04mA    60.38mA    32.12mA
-733.3mV  18.54mA    35mA       24.96mA
-618.2mV  9.672mA    10.45mA    13.13mA
-503mV    3.659mA    3.744mA    4.823mA
-272.7mV  33.98uA    110.8uA    33.63uA
3.585V    -5.325mA   -4.316mA   -6.779mA
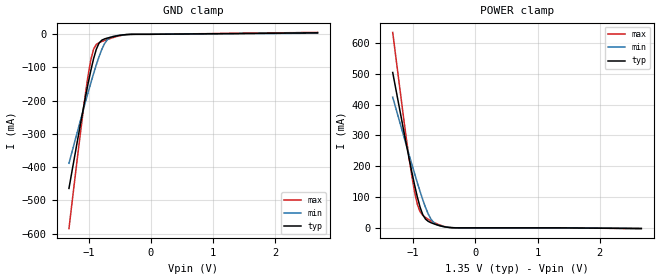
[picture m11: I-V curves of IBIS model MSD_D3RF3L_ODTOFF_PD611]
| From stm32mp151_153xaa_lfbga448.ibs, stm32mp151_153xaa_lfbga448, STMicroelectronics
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[Model] MSD_D3RF3L_ODTOFF_PD611
Model_type   Input
C_comp 2.439pF   2.355pF   2.563pF
Vinh = 810.000mV
Vinl = 540.000mV
[Temperature Range]   25.000   125.000   -40.000
[Voltage Range]   1.350V   1.283V   1.450V
[GND Clamp Reference]   0.00V   0.00V   0.00V
[POWER Clamp Reference]   1.350V   1.283V   1.450V
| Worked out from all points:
|   GND clamp passes 1 mA (typ) near -0.40 V on its own axis
|   POWER clamp passes 1 mA (typ) near -0.41 V on its own axis
[GND Clamp]
-1.318V   -464.1mA   -388.6mA   -585.3mA
-1.142V   -279.7mA   -265.4mA   -310mA
-1.055V   -191.1mA   -205.1mA   -181.8mA
-1.011V   -148.9mA   -175.7mA   -124.7mA
-966.7mV  -109.4mA   -146.8mA   -77.07mA
-922.7mV  -74.01mA   -118.9mA   -44.85mA
-878.8mV  -45.48mA   -92.25mA   -30.62mA
-834.9mV  -26.84mA   -67.6mA    -25.37mA
-790.9mV  -17.94mA   -45.92mA   -21.93mA
-703mV    -11.5mA    -16.72mA   -15.8mA
-527.3mV  -4.131mA   -3.477mA   -5.569mA
2.68V     4.387mA    3.412mA    5.694mA
[Power Clamp]
-1.33V    504.3mA    424.1mA    634.4mA
-1.111V   271.1mA    268mA      290.5mA
-1.023V   181.6mA    206.8mA    168.8mA
-978.8mV  139.5mA    176.7mA    117.4mA
-934.9mV  100.9mA    147.1mA    77.05mA
-890.9mV  67.81mA    118.5mA    52.64mA
-847mV    43.04mA    91.36mA    40.7mA
-803mV    28.45mA    66.48mA    33.66mA
-715.1mV  16.79mA    28.52mA    22.77mA
-671.2mV  13.27mA    17.55mA    18.07mA
-407.6mV  929uA      1.213mA    1.14mA
2.668V    -2.204mA   -1.835mA   -2.627mA
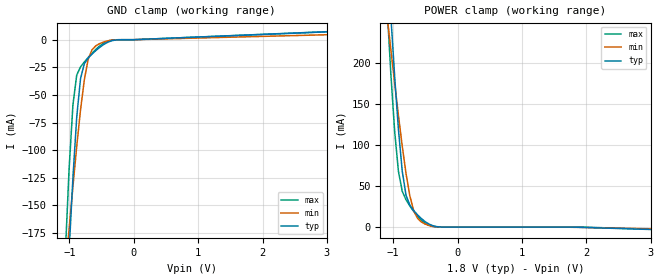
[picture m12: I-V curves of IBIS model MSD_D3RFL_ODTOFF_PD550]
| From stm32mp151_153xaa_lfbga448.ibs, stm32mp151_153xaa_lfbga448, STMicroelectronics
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[Model] MSD_D3RFL_ODTOFF_PD550
Model_type   Input
C_comp 2.379pF   2.318pF   2.526pF
Vinh = 1.440V
Vinl = 360.000mV
[Temperature Range]   25.000   125.000   -40.000
[Voltage Range]   1.800V   1.650V   1.950V
[GND Clamp Reference]   0.00V   0.00V   0.00V
[POWER Clamp Reference]   1.800V   1.650V   1.950V
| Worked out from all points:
|   GND clamp passes 1 mA (typ) near -0.34 V on its own axis
|   POWER clamp passes 1 mA (typ) near -0.35 V on its own axis
[GND Clamp]
-1.773V   -1.216A    -713.1mA   -1.315A
-1.064V   -264.2mA   -211.2mA   -194.3mA
-1.005V   -191.7mA   -171.6mA   -117.4mA
-945.5mV  -125.1mA   -133.1mA   -59.11mA
-886.4mV  -70.09mA   -96.65mA   -32.01mA
-827.3mV  -35.25mA   -63.57mA   -24.64mA
-768.2mV  -21.75mA   -36.26mA   -20.22mA
-709.1mV  -16.68mA   -17.98mA   -16.15mA
-650mV    -13.1mA    -9.218mA   -12.35mA
-531.8mV  -7.04mA    -3.584mA   -5.759mA
-236.4mV  -80.52uA   -39.93uA   -9.319uA
3.545V    8.384mA    5.294mA    8.573mA
[Power Clamp]
-1.745V   1.222A     726.3mA    1.305A
-1.095V   334.1mA    257.4mA    268.6mA
-1.036V   257.2mA    216.2mA    187mA
-977.3mV  184.1mA    175.7mA    117.2mA
-918.2mV  119.1mA    136.2mA    68.01mA
-859.1mV  68.26mA    98.83mA    43.69mA
-800mV    38.8mA     65.19mA    33.26mA
-740.9mV  26.85mA    38.08mA    25.74mA
-681.8mV  20.29mA    20.22mA    19.19mA
-563.6mV  10.51mA    6.399mA    8.669mA
-268.2mV  159uA      94.47uA    31.59uA
3.573V    -4.252mA   -2.934mA   -3.954mA
